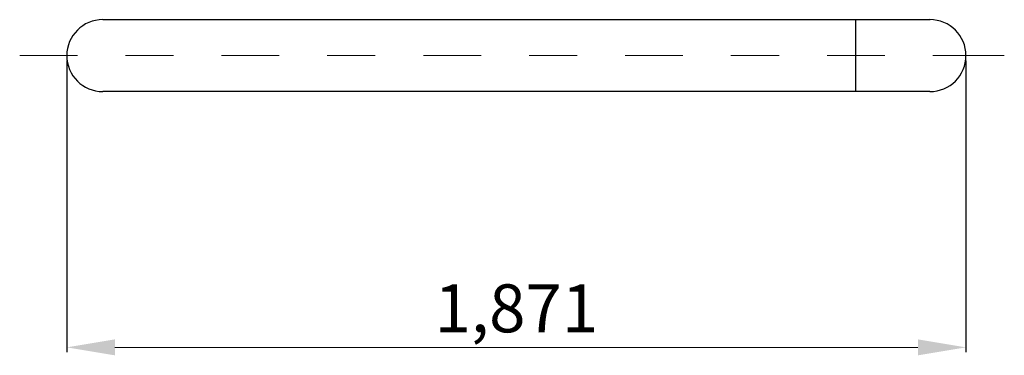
# Model space of a CAD drawing. Units: inches. Extents: x -0.2 to 1.85, y -2.62 to -1.93.
import ezdxf

# ---------------------------------------------------------------- set-up
doc = ezdxf.new("R2010")
doc.units = ezdxf.units.IN
doc.header["$LTSCALE"] = 0.01
doc.linetypes.add('ACAD_ISO10W100', pattern=[18, 12, -3, 0, -3])
doc.dimstyles.new('ISO-25', dxfattribs={"dimtxt": 0.1, "dimasz": 0.1, "dimexe": 0.01, "dimexo": 0.01, "dimgap": 0.01, "dimtad": 1, "dimdec": 3, "dimtxsty": 'Standard', "dimcen": 0.1, "dimadec": 0, "dimazin": 0, "dimtfac": 1, "dimtdec": 3, "dimtmove": 0, "dimatfit": 3, "dimfxl": 0, "dimlwd": 13, "dimarcsym": 0})

# ---------------------------------------------------------------- blocks, each defined once
blk = doc.blocks.new('*D5')
at = {"color": 0, "lineweight": -2, "ltscale": 0.13}
for p, q in [((-0.102, -2.01), (-0.102, -2.6182)), ((1.769, -2.01), (1.769, -2.6182))]:
    blk.add_line(p, q, dxfattribs=at)
at = {"color": 0, "lineweight": 13, "ltscale": 0.13}
blk.add_line((-0.002, -2.6082), (1.669, -2.6082), dxfattribs=at)
for points in [[(-0.002, -2.5915), (-0.002, -2.6248), (-0.102, -2.6082)], [(1.669, -2.5915), (1.669, -2.6248), (1.769, -2.6082)]]:
    blk.add_solid(points, dxfattribs=at)
at = {"layer": 'Defpoints', "color": 0, "lineweight": 13, "ltscale": 0.13}
for p in [(-0.102, -2), (1.769, -2), (1.769, -2.6082)]:
    blk.add_point(p, dxfattribs=at)
at = {"color": 0, "lineweight": 13, "ltscale": 0.13, "insert": (0.8335, -2.5398), "char_height": 0.1, "attachment_point": 5}
blk.add_mtext('1,871', dxfattribs=at)

msp = doc.modelspace()

# ---------------------------------------------------------------- linework, layer by layer
at = {"lineweight": 25, "ltscale": 0.13}
for p, q in [((-0.027, -1.925), (1.6946, -1.925)), ((1.539, -1.925), (1.539, -2.075)), ((1.694, -2.075), (-0.027, -2.075))]:
    msp.add_line(p, q, dxfattribs=at)
at = {"color": 1, "linetype": 'ACAD_ISO10W100', "lineweight": 13}
for p, q in [((-0.2, -2), (1.8, -2)), ((1.8, -2), (1.8488, -2))]:
    msp.add_line(p, q, dxfattribs=at)
at = {"lineweight": 25, "ltscale": 0.13}
for centre, start, end in [((-0.027, -2), 90, 270), ((1.694, -2), 270, 90)]:
    msp.add_arc(centre, 0.075, start, end, dxfattribs=at)

# ---------------------------------------------------------------- dimensions: what is measured, and where the dimension line sits
at = {"color": 3, "lineweight": 13, "ltscale": 0.13}
dim = msp.add_linear_dim(base=(1.769, -2.6082), p1=(-0.102, -2), p2=(1.769, -2), dimstyle='ISO-25', dxfattribs=at)
dim.commit()
dim.dimension.update_dxf_attribs({"geometry": '*D5', "text_midpoint": (0.8335, -2.5398)})

doc.saveas('drawing.dxf')
